VERSION 5.7 ;
  NOWIREEXTENSIONATPIN ON ;
  DIVIDERCHAR "/" ;
  BUSBITCHARS "[]" ;
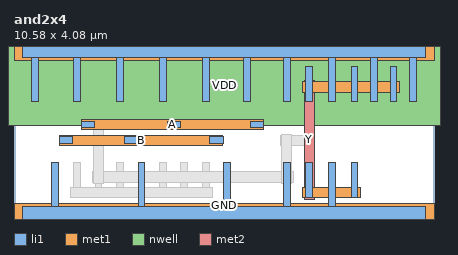
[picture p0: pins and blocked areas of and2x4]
MACRO and2x4
  CLASS BLOCK ;
  FOREIGN and2x4 ;
  ORIGIN 0.000 0.000 ;
  SIZE 10.580 BY 4.080 ;
  PIN A
    ANTENNAGATEAREA 1.982400 ;
    PORT
      LAYER li1 ;
        RECT 1.695 2.145 2.025 2.315 ;
        RECT 3.855 2.145 4.185 2.315 ;
        RECT 5.955 2.145 6.285 2.315 ;
      LAYER met1 ;
        RECT 1.700 2.100 6.280 2.360 ;
    END
  END A
  PIN B
    ANTENNAGATEAREA 1.982400 ;
    PORT
      LAYER li1 ;
        RECT 1.135 1.745 1.465 1.915 ;
        RECT 2.775 1.745 3.105 1.915 ;
        RECT 4.935 1.745 5.265 1.915 ;
      LAYER met1 ;
        RECT 1.140 1.700 5.260 1.960 ;
    END
  END B
  PIN VDD
    ANTENNADIFFAREA 5.576200 ;
    PORT
      LAYER nwell ;
        RECT -0.230 2.200 10.810 4.410 ;
      LAYER li1 ;
        RECT 0.210 3.915 10.370 4.245 ;
        RECT 0.445 2.800 0.615 3.915 ;
        RECT 1.505 2.800 1.675 3.915 ;
        RECT 2.585 2.800 2.755 3.915 ;
        RECT 3.665 2.800 3.835 3.915 ;
        RECT 4.745 2.800 4.915 3.915 ;
        RECT 5.785 2.800 5.955 3.915 ;
        RECT 6.785 2.800 6.955 3.915 ;
        RECT 7.925 2.800 8.095 3.915 ;
        RECT 8.985 2.800 9.155 3.915 ;
        RECT 9.965 2.800 10.135 3.915 ;
      LAYER met1 ;
        RECT 0.000 3.840 10.580 4.320 ;
    END
  END VDD
  PIN GND
    ANTENNADIFFAREA 4.152400 ;
    PORT
      LAYER li1 ;
        RECT 0.945 0.165 1.115 1.280 ;
        RECT 3.125 0.165 3.295 1.280 ;
        RECT 5.285 0.165 5.455 1.280 ;
        RECT 6.785 0.165 6.955 1.280 ;
        RECT 7.925 0.165 8.095 1.280 ;
        RECT 0.210 -0.165 10.370 0.165 ;
      LAYER met1 ;
        RECT 0.000 -0.240 10.580 0.240 ;
    END
  END GND
  PIN Y
    ANTENNADIFFAREA 1.281000 ;
    PORT
      LAYER li1 ;
        RECT 7.355 2.800 7.525 3.680 ;
        RECT 8.495 2.800 8.665 3.680 ;
        RECT 9.475 2.800 9.645 3.680 ;
        RECT 7.355 0.400 7.525 1.280 ;
        RECT 8.495 0.400 8.665 1.280 ;
      LAYER met1 ;
        RECT 7.280 3.040 9.720 3.300 ;
        RECT 7.280 0.380 8.740 0.640 ;
      LAYER met2 ;
        RECT 7.310 0.350 7.570 3.330 ;
    END
  END Y
  OBS
      LAYER li1 ;
        RECT 0.945 2.800 1.115 3.680 ;
        RECT 2.045 2.800 2.215 3.680 ;
        RECT 3.125 2.800 3.295 3.680 ;
        RECT 4.205 2.800 4.375 3.680 ;
        RECT 5.285 2.800 5.455 3.680 ;
        RECT 6.285 2.800 6.455 3.680 ;
        RECT 6.990 1.745 7.320 1.915 ;
        RECT 1.505 0.400 1.675 1.280 ;
        RECT 2.045 0.400 2.215 1.280 ;
        RECT 2.585 0.400 2.755 1.280 ;
        RECT 3.665 0.400 3.835 1.280 ;
        RECT 4.205 0.400 4.375 1.280 ;
        RECT 4.745 0.400 4.915 1.280 ;
      LAYER met1 ;
        RECT 0.870 3.040 6.530 3.300 ;
        RECT 6.710 1.700 7.315 1.960 ;
        RECT 1.970 0.780 7.030 1.040 ;
        RECT 1.430 0.380 4.990 0.640 ;
      LAYER met2 ;
        RECT 2.000 0.750 2.260 3.330 ;
        RECT 6.740 0.750 7.000 1.990 ;
  END
END and2x4
END LIBRARY

